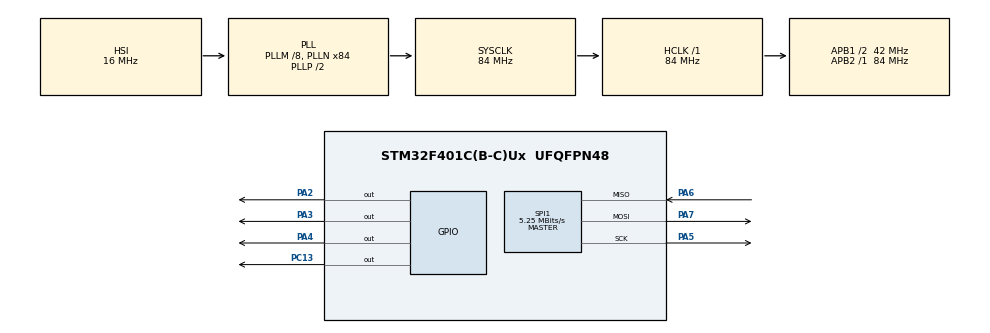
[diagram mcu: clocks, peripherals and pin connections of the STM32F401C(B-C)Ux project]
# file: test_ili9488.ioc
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Mcu.Family=STM32F4
Mcu.Name=STM32F401C(B-C)Ux
Mcu.Package=UFQFPN48
NVIC.PriorityGroup=NVIC_PRIORITYGROUP_4
PA13.Mode=Serial_Wire
PA13.Signal=SYS_JTMS-SWDIO
PA14.Mode=Serial_Wire
PA14.Signal=SYS_JTCK-SWCLK
PA2.GPIO_Speed=GPIO_SPEED_FREQ_VERY_HIGH
PA2.Signal=GPIO_Output
PA3.GPIO_Speed=GPIO_SPEED_FREQ_VERY_HIGH
PA3.Signal=GPIO_Output
PA4.GPIO_Speed=GPIO_SPEED_FREQ_VERY_HIGH
PA4.Signal=GPIO_Output
PA5.Mode=Full_Duplex_Master
PA5.Signal=SPI1_SCK
PA6.Mode=Full_Duplex_Master
PA6.Signal=SPI1_MISO
PA7.Mode=Full_Duplex_Master
PA7.Signal=SPI1_MOSI
PC13-ANTI_TAMP.Signal=GPIO_Output
ProjectManager.HeapSize=0x200
ProjectManager.StackSize=0x400
ProjectManager.TargetToolchain=Makefile
RCC.48MHZClocksFreq_Value=42000000
RCC.AHBFreq_Value=84000000
RCC.APB1CLKDivider=RCC_HCLK_DIV2
RCC.APB1Freq_Value=42000000
RCC.APB1TimFreq_Value=84000000
RCC.APB2Freq_Value=84000000
RCC.APB2TimFreq_Value=84000000
RCC.CortexFreq_Value=84000000
RCC.HCLKFreq_Value=84000000
RCC.HSE_VALUE=25000000
RCC.HSI_VALUE=16000000
RCC.LSE_VALUE=32768
RCC.PLLM=8
RCC.PLLN=84
RCC.SYSCLKFreq_VALUE=84000000
RCC.SYSCLKSource=RCC_SYSCLKSOURCE_PLLCLK
RCC.VCOOutputFreq_Value=168000000
SPI1.BaudRatePrescaler=SPI_BAUDRATEPRESCALER_16
SPI1.CalculateBaudRate=5.25 MBits/s
SPI1.Direction=SPI_DIRECTION_2LINES
SPI1.Mode=SPI_MODE_MASTER
SPI1.VirtualType=VM_MASTER
board=custom

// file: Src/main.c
/* USER CODE BEGIN Header */
/**
  ******************************************************************************
  * @file           : main.c
  * @brief          : Main program body
  ******************************************************************************
  * @attention
  *
  * <h2><center>&copy; Copyright (c) 2020 STMicroelectronics.
  * All rights reserved.</center></h2>
  *
  * This software component is licensed by ST under BSD 3-Clause license,
  * the "License"; You may not use this file except in compliance with the
  * License. You may obtain a copy of the License at:
  *                        opensource.org/licenses/BSD-3-Clause
  *
  ******************************************************************************
  */
/* USER CODE END Header */

#include "main.h"
#include "ili9488.h"

SPI_HandleTypeDef hspi1;

void SystemClock_Config(void);
static void MX_GPIO_Init(void);
static void MX_SPI1_Init(void);

int main(void)
{

  /* MCU Configuration--------------------------------------------------------*/

  /* Reset of all peripherals, Initializes the Flash interface and the Systick. */
  HAL_Init();

  /* Configure the system clock */
  SystemClock_Config();

  /* Initialize all configured peripherals */
  MX_GPIO_Init();
  MX_SPI1_Init();
  /* USER CODE BEGIN 2 */

  TFT_Init();
  DrawPixel (20, 100, ILI9488_RED);
  DrawFastVLine (50, 5, 200, ILI9488_RED);
  DrawFastVLine (51, 5, 200, ILI9488_GREEN);
  DrawFastVLine (52, 5, 200, ILI9488_BLUE);
  DrawFastVLine (53, 5, 200, ILI9488_RED);
  DrawFastVLine (54, 5, 200, ILI9488_GREEN);
  DrawFastVLine (55, 5, 200, ILI9488_BLUE);

  DrawFastVLine (200, 5, 200, ILI9488_RED);
  DrawFastVLine (201, 5, 200, ILI9488_GREEN);
  DrawFastVLine (202, 5, 200, ILI9488_BLUE);
  DrawFastVLine (203, 5, 200, ILI9488_RED);
  DrawFastVLine (204, 5, 200, ILI9488_GREEN);
  DrawFastVLine (205, 5, 200, ILI9488_BLUE);

  DrawFill (0, 0, 50, 50, ILI9488_BLUE);

  HAL_GPIO_WritePin(GPIOB, GPIO_PIN_4 | GPIO_PIN_5, GPIO_PIN_SET);
  HAL_GPIO_WritePin(GPIOA, GPIO_PIN_3, GPIO_PIN_SET);

  /* USER CODE END 2 */

  /* Infinite loop */
  while (1)
  {

    /* USER CODE BEGIN 3 */
    HAL_GPIO_TogglePin(GPIOC, GPIO_PIN_13);
    HAL_Delay(500);
  }
  /* USER CODE END 3 */
}

void SystemClock_Config(void)
{
  RCC_OscInitTypeDef RCC_OscInitStruct = {0};
  RCC_ClkInitTypeDef RCC_ClkInitStruct = {0};

  /** Configure the main internal regulator output voltage
  */
  __HAL_RCC_PWR_CLK_ENABLE();
  __HAL_PWR_VOLTAGESCALING_CONFIG(PWR_REGULATOR_VOLTAGE_SCALE2);
  /** Initializes the CPU, AHB and APB busses clocks
  */
  RCC_OscInitStruct.OscillatorType = RCC_OSCILLATORTYPE_HSI;
  RCC_OscInitStruct.HSIState = RCC_HSI_ON;
  RCC_OscInitStruct.HSICalibrationValue = RCC_HSICALIBRATION_DEFAULT;
  RCC_OscInitStruct.PLL.PLLState = RCC_PLL_ON;
  RCC_OscInitStruct.PLL.PLLSource = RCC_PLLSOURCE_HSI;
  RCC_OscInitStruct.PLL.PLLM = 8;
  RCC_OscInitStruct.PLL.PLLN = 84;
  RCC_OscInitStruct.PLL.PLLP = RCC_PLLP_DIV2;
  RCC_OscInitStruct.PLL.PLLQ = 4;
  if (HAL_RCC_OscConfig(&RCC_OscInitStruct) != HAL_OK)
  {
    Error_Handler();
  }
  /** Initializes the CPU, AHB and APB busses clocks
  */
  RCC_ClkInitStruct.ClockType = RCC_CLOCKTYPE_HCLK|RCC_CLOCKTYPE_SYSCLK
                              |RCC_CLOCKTYPE_PCLK1|RCC_CLOCKTYPE_PCLK2;
  RCC_ClkInitStruct.SYSCLKSource = RCC_SYSCLKSOURCE_PLLCLK;
  RCC_ClkInitStruct.AHBCLKDivider = RCC_SYSCLK_DIV1;
  RCC_ClkInitStruct.APB1CLKDivider = RCC_HCLK_DIV2;
  RCC_ClkInitStruct.APB2CLKDivider = RCC_HCLK_DIV1;

  if (HAL_RCC_ClockConfig(&RCC_ClkInitStruct, FLASH_LATENCY_2) != HAL_OK)
  {
    Error_Handler();
  }
}

static void MX_SPI1_Init(void)
{

  /* SPI1 parameter configuration*/
  hspi1.Instance = SPI1;
  hspi1.Init.Mode = SPI_MODE_MASTER;
  hspi1.Init.Direction = SPI_DIRECTION_2LINES;
  hspi1.Init.DataSize = SPI_DATASIZE_8BIT;
  hspi1.Init.CLKPolarity = SPI_POLARITY_LOW;
  hspi1.Init.CLKPhase = SPI_PHASE_1EDGE;
  hspi1.Init.NSS = SPI_NSS_SOFT;
  hspi1.Init.BaudRatePrescaler = SPI_BAUDRATEPRESCALER_16;
  hspi1.Init.FirstBit = SPI_FIRSTBIT_MSB;
  hspi1.Init.TIMode = SPI_TIMODE_DISABLE;
  hspi1.Init.CRCCalculation = SPI_CRCCALCULATION_DISABLE;
  hspi1.Init.CRCPolynomial = 10;
  if (HAL_SPI_Init(&hspi1) != HAL_OK)
  {
    Error_Handler();
  }

}

static void MX_GPIO_Init(void)
{
  GPIO_InitTypeDef GPIO_InitStruct = {0};

  /* GPIO Ports Clock Enable */
  __HAL_RCC_GPIOC_CLK_ENABLE();
  __HAL_RCC_GPIOA_CLK_ENABLE();
  __HAL_RCC_GPIOB_CLK_ENABLE();

  /*Configure GPIO pin Output Level */
  HAL_GPIO_WritePin(GPIOC, GPIO_PIN_13, GPIO_PIN_RESET);

  /*Configure GPIO pin Output Level */
  HAL_GPIO_WritePin(GPIOA, GPIO_PIN_3 | GPIO_PIN_4, GPIO_PIN_RESET);

  /*Configure GPIO pin : PC13 */
  GPIO_InitStruct.Pin = GPIO_PIN_13;
  GPIO_InitStruct.Mode = GPIO_MODE_OUTPUT_PP;
  GPIO_InitStruct.Pull = GPIO_NOPULL;
  GPIO_InitStruct.Speed = GPIO_SPEED_FREQ_LOW;
  HAL_GPIO_Init(GPIOC, &GPIO_InitStruct);

  /*Configure GPIO pins : PA3 PA4 */
  GPIO_InitStruct.Pin = GPIO_PIN_3 | GPIO_PIN_4;
  GPIO_InitStruct.Mode = GPIO_MODE_OUTPUT_PP;
  GPIO_InitStruct.Pull = GPIO_NOPULL;
  GPIO_InitStruct.Speed = GPIO_SPEED_FREQ_VERY_HIGH;
  HAL_GPIO_Init(GPIOA, &GPIO_InitStruct);

  /*Configure GPIO pin : PB0 PB1 PB4 PB5 */
  GPIO_InitStruct.Pin = GPIO_PIN_0 | GPIO_PIN_1 | GPIO_PIN_4 | GPIO_PIN_5;
  GPIO_InitStruct.Mode = GPIO_MODE_OUTPUT_PP;
  GPIO_InitStruct.Pull = GPIO_NOPULL;
  GPIO_InitStruct.Speed = GPIO_SPEED_FREQ_LOW;
  HAL_GPIO_Init(GPIOB, &GPIO_InitStruct);

}

void Error_Handler(void)
{
}

/************************ (C) COPYRIGHT STMicroelectronics *****END OF FILE****/
